VERSION 5.8 ;
BUSBITCHARS "[]" ;
DIVIDERCHAR "/" ;
UNITS
    DATABASE MICRONS 1000 ;
END UNITS

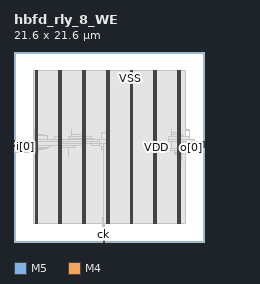
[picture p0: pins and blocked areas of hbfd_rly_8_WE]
MACRO hbfd_rly_8_WE
  FOREIGN hbfd_rly_8_WE 0 0 ;
  CLASS BLOCK ;
  SIZE 21.6 BY 21.6 ;
  PIN ck
    DIRECTION INPUT ;
    USE SIGNAL ;
    PORT
      LAYER M5 ;
        RECT  10.128 0 10.152 0.084 ;
    END
  END ck
  PIN i[0]
    DIRECTION INPUT ;
    USE SIGNAL ;
    PORT
      LAYER M4 ;
        RECT  0 10.896 0.084 10.92 ;
    END
  END i[0]
  PIN i[1]
    DIRECTION INPUT ;
    USE SIGNAL ;
    PORT
      LAYER M4 ;
        RECT  0 10.992 0.084 11.016 ;
    END
  END i[1]
  PIN i[2]
    DIRECTION INPUT ;
    USE SIGNAL ;
    PORT
      LAYER M4 ;
        RECT  0 11.088 0.084 11.112 ;
    END
  END i[2]
  PIN i[3]
    DIRECTION INPUT ;
    USE SIGNAL ;
    PORT
      LAYER M4 ;
        RECT  0 11.184 0.084 11.208 ;
    END
  END i[3]
  PIN i[4]
    DIRECTION INPUT ;
    USE SIGNAL ;
    PORT
      LAYER M4 ;
        RECT  0 11.28 0.084 11.304 ;
    END
  END i[4]
  PIN i[5]
    DIRECTION INPUT ;
    USE SIGNAL ;
    PORT
      LAYER M4 ;
        RECT  0 11.376 0.084 11.4 ;
    END
  END i[5]
  PIN i[6]
    DIRECTION INPUT ;
    USE SIGNAL ;
    PORT
      LAYER M4 ;
        RECT  0 11.472 0.084 11.496 ;
    END
  END i[6]
  PIN i[7]
    DIRECTION INPUT ;
    USE SIGNAL ;
    PORT
      LAYER M4 ;
        RECT  0 11.568 0.084 11.592 ;
    END
  END i[7]
  PIN o[0]
    DIRECTION OUTPUT ;
    USE SIGNAL ;
    PORT
      LAYER M4 ;
        RECT  21.516 10.704 21.6 10.728 ;
    END
  END o[0]
  PIN o[1]
    DIRECTION OUTPUT ;
    USE SIGNAL ;
    PORT
      LAYER M4 ;
        RECT  21.516 10.8 21.6 10.824 ;
    END
  END o[1]
  PIN o[2]
    DIRECTION OUTPUT ;
    USE SIGNAL ;
    PORT
      LAYER M4 ;
        RECT  21.516 10.896 21.6 10.92 ;
    END
  END o[2]
  PIN o[3]
    DIRECTION OUTPUT ;
    USE SIGNAL ;
    PORT
      LAYER M4 ;
        RECT  21.516 10.992 21.6 11.016 ;
    END
  END o[3]
  PIN o[4]
    DIRECTION OUTPUT ;
    USE SIGNAL ;
    PORT
      LAYER M4 ;
        RECT  21.516 11.088 21.6 11.112 ;
    END
  END o[4]
  PIN o[5]
    DIRECTION OUTPUT ;
    USE SIGNAL ;
    PORT
      LAYER M4 ;
        RECT  21.516 11.184 21.6 11.208 ;
    END
  END o[5]
  PIN o[6]
    DIRECTION OUTPUT ;
    USE SIGNAL ;
    PORT
      LAYER M4 ;
        RECT  21.516 11.28 21.6 11.304 ;
    END
  END o[6]
  PIN o[7]
    DIRECTION OUTPUT ;
    USE SIGNAL ;
    PORT
      LAYER M4 ;
        RECT  21.516 11.376 21.6 11.4 ;
    END
  END o[7]
  PIN rs
    DIRECTION INPUT ;
    USE SIGNAL ;
    PORT
      LAYER M5 ;
        RECT  10.224 0 10.248 0.084 ;
    END
  END rs
  PIN VDD
    DIRECTION INOUT ;
    USE POWER ;
    PORT
      LAYER M5 ;
        RECT  18.792 2.151 18.912 19.449 ;
        RECT  16.092 2.151 16.212 19.449 ;
        RECT  13.392 2.151 13.512 19.449 ;
        RECT  10.692 2.151 10.812 19.449 ;
        RECT  7.992 2.151 8.112 19.449 ;
        RECT  5.292 2.151 5.412 19.449 ;
        RECT  2.592 2.151 2.712 19.449 ;
    END
  END VDD
  PIN VSS
    DIRECTION INOUT ;
    USE GROUND ;
    PORT
      LAYER M5 ;
        RECT  18.6 2.137 18.72 19.463 ;
        RECT  15.9 2.137 16.02 19.463 ;
        RECT  13.2 2.137 13.32 19.463 ;
        RECT  10.5 2.137 10.62 19.463 ;
        RECT  7.8 2.137 7.92 19.463 ;
        RECT  5.1 2.137 5.22 19.463 ;
        RECT  2.4 2.137 2.52 19.463 ;
    END
  END VSS
  # OT_OBS_CLOSED layer=M5 d_um=1.536 added=0
  OBS
    LAYER RVTN ;
     RECT  2.16 2.16 19.44 2.295 ;
     RECT  2.16 2.565 19.44 2.835 ;
     RECT  2.16 3.105 19.44 3.375 ;
     RECT  2.16 3.645 19.44 3.915 ;
     RECT  2.16 4.185 19.44 4.455 ;
     RECT  2.16 4.725 19.44 4.995 ;
     RECT  2.16 5.265 19.44 5.535 ;
     RECT  2.16 5.805 19.44 6.075 ;
     RECT  2.16 6.345 19.44 6.615 ;
     RECT  2.16 6.885 19.44 7.155 ;
     RECT  2.16 7.425 19.44 7.695 ;
     RECT  2.16 7.965 19.44 8.235 ;
     RECT  2.16 8.505 19.44 8.775 ;
     RECT  2.16 9.045 19.44 9.315 ;
     RECT  2.16 9.585 19.44 9.855 ;
     RECT  2.16 10.125 19.44 10.395 ;
     RECT  2.16 10.665 19.44 10.935 ;
     RECT  2.16 11.205 19.44 11.475 ;
     RECT  2.16 11.745 19.44 12.015 ;
     RECT  2.16 12.285 19.44 12.555 ;
     RECT  2.16 12.825 19.44 13.095 ;
     RECT  2.16 13.365 19.44 13.635 ;
     RECT  2.16 13.905 19.44 14.175 ;
     RECT  2.16 14.445 19.44 14.715 ;
     RECT  2.16 14.985 19.44 15.255 ;
     RECT  2.16 15.525 19.44 15.795 ;
     RECT  2.16 16.065 19.44 16.335 ;
     RECT  2.16 16.605 19.44 16.875 ;
     RECT  2.16 17.145 19.44 17.415 ;
     RECT  2.16 17.685 19.44 17.955 ;
     RECT  2.16 18.225 19.44 18.495 ;
     RECT  2.16 18.765 19.44 19.035 ;
     RECT  2.16 19.305 19.44 19.44 ;
    LAYER RVTP ;
     RECT  2.16 2.295 19.44 2.565 ;
     RECT  2.16 2.835 19.44 3.105 ;
     RECT  2.16 3.375 19.44 3.645 ;
     RECT  2.16 3.915 19.44 4.185 ;
     RECT  2.16 4.455 19.44 4.725 ;
     RECT  2.16 4.995 19.44 5.265 ;
     RECT  2.16 5.535 19.44 5.805 ;
     RECT  2.16 6.075 19.44 6.345 ;
     RECT  2.16 6.615 19.44 6.885 ;
     RECT  2.16 7.155 19.44 7.425 ;
     RECT  2.16 7.695 19.44 7.965 ;
     RECT  2.16 8.235 19.44 8.505 ;
     RECT  2.16 8.775 19.44 9.045 ;
     RECT  2.16 9.315 19.44 9.585 ;
     RECT  2.16 9.855 19.44 10.125 ;
     RECT  2.16 10.395 19.44 10.665 ;
     RECT  2.16 10.935 19.44 11.205 ;
     RECT  2.16 11.475 19.44 11.745 ;
     RECT  2.16 12.015 19.44 12.285 ;
     RECT  2.16 12.555 19.44 12.825 ;
     RECT  2.16 13.095 19.44 13.365 ;
     RECT  2.16 13.635 19.44 13.905 ;
     RECT  2.16 14.175 19.44 14.445 ;
     RECT  2.16 14.715 19.44 14.985 ;
     RECT  2.16 15.255 19.44 15.525 ;
     RECT  2.16 15.795 19.44 16.065 ;
     RECT  2.16 16.335 19.44 16.605 ;
     RECT  2.16 16.875 19.44 17.145 ;
     RECT  2.16 17.415 19.44 17.685 ;
     RECT  2.16 17.955 19.44 18.225 ;
     RECT  2.16 18.495 19.44 18.765 ;
     RECT  2.16 19.035 19.44 19.305 ;
    LAYER M1 ;
     RECT  2.16 2.151 19.44 19.449 ;
    LAYER M2 ;
     RECT  0.103 10.17 0.139 10.188 ;
     RECT  0.139 10.17 2.16 10.458 ;
     RECT  2.16 2.151 19.44 19.449 ;
     RECT  19.44 12.726 19.931 12.744 ;
     RECT  19.44 11.016 20.507 11.664 ;
    LAYER M3 ;
     RECT  10.116 1.723 10.134 2.143 ;
     RECT  2.415 2.143 2.505 2.413 ;
     RECT  5.115 2.143 5.205 2.413 ;
     RECT  7.815 2.143 7.905 2.413 ;
     RECT  10.116 2.143 10.605 2.413 ;
     RECT  13.215 2.143 13.305 2.413 ;
     RECT  15.915 2.143 16.005 2.413 ;
     RECT  18.615 2.143 18.705 2.413 ;
     RECT  10.116 2.413 10.797 2.795 ;
     RECT  10.332 2.795 10.797 5.341 ;
     RECT  18.615 2.413 18.897 9.247 ;
     RECT  18.615 9.247 19.098 9.895 ;
     RECT  18.36 9.895 19.098 9.931 ;
     RECT  18.252 9.931 19.098 10.093 ;
     RECT  2.415 2.413 2.697 10.201 ;
     RECT  18.252 10.093 19.242 10.201 ;
     RECT  0.108 10.165 0.126 10.435 ;
     RECT  18.252 10.201 19.314 10.435 ;
     RECT  2.415 10.201 2.754 10.471 ;
     RECT  10.224 5.341 10.797 10.471 ;
     RECT  17.784 10.435 19.314 10.589 ;
     RECT  2.415 10.471 3.33 10.597 ;
     RECT  7.815 2.413 8.097 10.597 ;
     RECT  2.415 10.597 3.798 10.705 ;
     RECT  5.115 2.413 5.397 10.705 ;
     RECT  6.228 9.751 6.246 10.705 ;
     RECT  5.115 10.705 6.246 10.741 ;
     RECT  9.936 10.471 10.797 10.895 ;
     RECT  0.108 10.435 0.162 10.925 ;
     RECT  2.415 10.705 4.086 10.939 ;
     RECT  2.415 10.939 4.23 10.975 ;
     RECT  8.964 10.939 8.982 10.975 ;
     RECT  2.304 10.975 4.23 11.011 ;
     RECT  5.115 10.741 6.822 11.011 ;
     RECT  7.74 10.597 8.097 11.011 ;
     RECT  8.82 10.975 8.982 11.011 ;
     RECT  0.144 10.925 0.162 11.117 ;
     RECT  2.304 11.011 8.097 11.371 ;
     RECT  8.82 11.011 9.702 11.371 ;
     RECT  17.856 10.589 19.314 11.371 ;
     RECT  20.484 10.987 20.502 11.371 ;
     RECT  17.856 11.371 20.502 11.407 ;
     RECT  2.268 11.371 9.702 11.669 ;
     RECT  17.568 11.407 20.502 11.669 ;
     RECT  10.515 10.895 10.797 11.677 ;
     RECT  2.268 11.669 5.397 11.705 ;
     RECT  6.192 11.669 8.982 11.741 ;
     RECT  4.572 11.705 5.397 11.939 ;
     RECT  6.192 11.741 8.766 11.939 ;
     RECT  17.568 11.669 19.926 11.939 ;
     RECT  6.48 11.939 8.766 11.975 ;
     RECT  2.304 11.705 3.798 12.119 ;
     RECT  2.304 12.119 3.402 12.209 ;
     RECT  6.552 11.975 8.097 12.209 ;
     RECT  17.856 11.939 19.134 12.209 ;
     RECT  9.9 11.677 10.797 12.479 ;
     RECT  17.856 12.209 18.897 12.479 ;
     RECT  6.552 12.209 6.57 12.749 ;
     RECT  19.908 11.939 19.926 12.749 ;
     RECT  2.304 12.209 2.697 12.785 ;
     RECT  17.856 12.479 17.874 12.785 ;
     RECT  2.415 12.785 2.697 19.187 ;
     RECT  5.115 11.939 5.397 19.187 ;
     RECT  7.815 12.209 8.097 19.187 ;
     RECT  10.515 12.479 10.797 19.187 ;
     RECT  13.215 2.413 13.497 19.187 ;
     RECT  15.915 2.413 16.197 19.187 ;
     RECT  18.615 12.479 18.897 19.187 ;
     RECT  2.415 19.187 2.505 19.457 ;
     RECT  5.115 19.187 5.205 19.457 ;
     RECT  7.815 19.187 7.905 19.457 ;
     RECT  10.515 19.187 10.605 19.457 ;
     RECT  13.215 19.187 13.305 19.457 ;
     RECT  15.915 19.187 16.005 19.457 ;
     RECT  18.615 19.187 18.705 19.457 ;
    LAYER M4 ;
     RECT  0.06 10.896 0.137 11.592 ;
     RECT  0.137 10.992 2.408 11.592 ;
     RECT  2.408 2.148 2.512 19.452 ;
     RECT  2.512 2.418 2.704 19.182 ;
     RECT  2.704 11.616 4.345 11.64 ;
     RECT  4.345 11.424 5.108 11.64 ;
     RECT  5.108 2.148 5.212 19.452 ;
     RECT  5.212 2.418 5.404 19.182 ;
     RECT  5.404 11.184 7.808 11.448 ;
     RECT  7.808 2.148 7.912 19.452 ;
     RECT  7.912 2.418 8.104 19.182 ;
     RECT  10.105 1.728 10.259 1.752 ;
     RECT  8.104 11.184 10.508 11.208 ;
     RECT  10.508 2.148 10.612 19.452 ;
     RECT  10.612 2.418 10.804 19.182 ;
     RECT  13.208 2.148 13.312 19.452 ;
     RECT  13.312 2.418 13.504 19.182 ;
     RECT  15.908 2.148 16.012 19.452 ;
     RECT  16.012 2.418 16.204 19.182 ;
     RECT  18.608 2.148 18.712 19.452 ;
     RECT  18.712 2.418 18.904 19.182 ;
     RECT  18.904 10.704 19.897 10.92 ;
     RECT  19.897 10.704 21.564 11.4 ;
    LAYER M5 ;
     RECT  10.128 0.016 10.248 2.137 ;
     RECT  2.4 2.137 2.52 2.151 ;
     RECT  5.1 2.137 5.22 2.151 ;
     RECT  7.8 2.137 7.92 2.151 ;
     RECT  10.128 2.137 10.62 2.151 ;
     RECT  13.2 2.137 13.32 2.151 ;
     RECT  15.9 2.137 16.02 2.151 ;
     RECT  18.6 2.137 18.72 2.151 ;
     RECT  10.128 2.151 10.812 11.219 ;
     RECT  2.4 2.151 2.712 19.449 ;
     RECT  5.1 2.151 5.412 19.449 ;
     RECT  7.8 2.151 8.112 19.449 ;
     RECT  10.5 11.219 10.812 19.449 ;
     RECT  13.2 2.151 13.512 19.449 ;
     RECT  15.9 2.151 16.212 19.449 ;
     RECT  18.6 2.151 18.912 19.449 ;
     RECT  2.4 19.449 2.52 19.463 ;
     RECT  5.1 19.449 5.22 19.463 ;
     RECT  7.8 19.449 7.92 19.463 ;
     RECT  10.5 19.449 10.62 19.463 ;
     RECT  13.2 19.449 13.32 19.463 ;
     RECT  15.9 19.449 16.02 19.463 ;
     RECT  18.6 19.449 18.72 19.463 ;
  END
END hbfd_rly_8_WE
END LIBRARY
